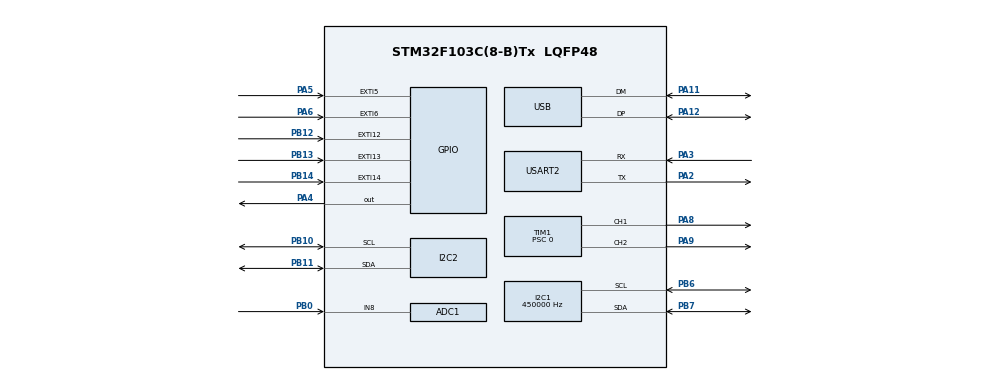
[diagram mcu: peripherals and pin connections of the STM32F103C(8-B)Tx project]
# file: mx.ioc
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ADC1.Channel-2\#ChannelRegularConversion=ADC_CHANNEL_8
ADC1.NbrOfConversionFlag=1
ADC1.Rank-2\#ChannelRegularConversion=1
ADC1.SamplingTime-2\#ChannelRegularConversion=ADC_SAMPLETIME_1CYCLE_5
ADC1.master=1
Dma.Request0=USART2_RX
Dma.USART2_RX.0.Direction=DMA_PERIPH_TO_MEMORY
Dma.USART2_RX.0.Instance=DMA1_Channel6
Dma.USART2_RX.0.MemDataAlignment=DMA_MDATAALIGN_BYTE
Dma.USART2_RX.0.MemInc=DMA_MINC_ENABLE
Dma.USART2_RX.0.Mode=DMA_NORMAL
Dma.USART2_RX.0.PeriphDataAlignment=DMA_PDATAALIGN_BYTE
Dma.USART2_RX.0.PeriphInc=DMA_PINC_DISABLE
Dma.USART2_RX.0.Priority=DMA_PRIORITY_MEDIUM
I2C1.ClockSpeed=450000
I2C1.I2C_Mode=I2C_Fast
Mcu.Family=STM32F1
Mcu.Name=STM32F103C(8-B)Tx
Mcu.Package=LQFP48
NVIC.ADC1_2_IRQn=true\:0\:0\:false\:false\:true\:true\:true\:true
NVIC.DMA1_Channel6_IRQn=true\:0\:0\:false\:false\:true\:false\:true\:true
NVIC.EXTI15_10_IRQn=true\:0\:0\:false\:false\:true\:true\:true\:true
NVIC.EXTI9_5_IRQn=true\:0\:0\:false\:false\:true\:true\:true\:true
NVIC.I2C1_ER_IRQn=true\:0\:0\:false\:false\:true\:true\:true\:true
NVIC.I2C1_EV_IRQn=true\:0\:0\:false\:false\:true\:true\:true\:true
NVIC.PriorityGroup=NVIC_PRIORITYGROUP_4
NVIC.TIM3_IRQn=true\:0\:0\:false\:false\:true\:true\:true\:true
NVIC.TIM4_IRQn=true\:0\:0\:false\:false\:true\:true\:true\:true
NVIC.USART2_IRQn=true\:0\:0\:false\:false\:true\:true\:true\:true
NVIC.USB_LP_CAN1_RX0_IRQn=true\:0\:0\:false\:false\:true\:false\:true\:true
PA11.Mode=Device
PA11.Signal=USB_DM
PA12.Mode=Device
PA12.Signal=USB_DP
PA13.Mode=Serial_Wire
PA13.Signal=SYS_JTMS-SWDIO
PA14.Mode=Serial_Wire
PA14.Signal=SYS_JTCK-SWCLK
PA2.Mode=Asynchronous
PA2.Signal=USART2_TX
PA3.Mode=Asynchronous
PA3.Signal=USART2_RX
PA4.GPIO_PuPd=GPIO_NOPULL
PA4.PinState=GPIO_PIN_RESET
PA4.Signal=GPIO_Output
PA5.GPIO_ModeDefaultEXTI=GPIO_MODE_IT_RISING_FALLING
PA5.GPIO_PuPd=GPIO_PULLUP
PA5.Signal=GPXTI5
PA6.GPIO_ModeDefaultEXTI=GPIO_MODE_IT_RISING_FALLING
PA6.GPIO_PuPd=GPIO_PULLUP
PA6.Signal=GPXTI6
PA8.GPIO_Speed=GPIO_SPEED_FREQ_MEDIUM
PA8.Signal=S_TIM1_CH1
PA9.GPIO_Speed=GPIO_SPEED_FREQ_MEDIUM
PA9.Signal=S_TIM1_CH2
PB0.Signal=ADCx_IN8
PB10.Mode=I2C
PB10.Signal=I2C2_SCL
PB11.Mode=I2C
PB11.Signal=I2C2_SDA
PB12.GPIO_ModeDefaultEXTI=GPIO_MODE_IT_RISING_FALLING
PB12.GPIO_PuPd=GPIO_PULLUP
PB12.Signal=GPXTI12
PB13.GPIO_ModeDefaultEXTI=GPIO_MODE_IT_RISING_FALLING
PB13.GPIO_PuPd=GPIO_PULLUP
PB13.Signal=GPXTI13
PB14.GPIO_ModeDefaultEXTI=GPIO_MODE_IT_RISING_FALLING
PB14.GPIO_PuPd=GPIO_PULLUP
PB14.Signal=GPXTI14
PB6.Mode=I2C
PB6.Signal=I2C1_SCL
PB7.Mode=I2C
PB7.Signal=I2C1_SDA
PD0-OSC_IN.Mode=HSE-External-Oscillator
PD0-OSC_IN.Signal=RCC_OSC_IN
PD1-OSC_OUT.Mode=HSE-External-Oscillator
PD1-OSC_OUT.Signal=RCC_OSC_OUT
ProjectManager.HeapSize=0x200
ProjectManager.StackSize=0x400
ProjectManager.TargetToolchain=CMake
RCC.ADCPresc=RCC_ADCPCLK2_DIV6
RCC.AHBFreq_Value=72000000
RCC.APB1CLKDivider=RCC_HCLK_DIV2
RCC.APB1Freq_Value=36000000
RCC.APB1TimFreq_Value=72000000
RCC.APB2Freq_Value=72000000
RCC.APB2TimFreq_Value=72000000
RCC.HCLKFreq_Value=72000000
RCC.PLLMUL=RCC_PLL_MUL9
RCC.PLLSourceVirtual=RCC_PLLSOURCE_HSE
RCC.SYSCLKFreq_VALUE=72000000
RCC.SYSCLKSource=RCC_SYSCLKSOURCE_PLLCLK
RCC.USBFreq_Value=48000000
RCC.USBPrescaler=RCC_USBCLKSOURCE_PLL_DIV1_5
SH.ADCx_IN8.0=ADC1_IN8,IN8
SH.S_TIM1_CH1.0=TIM1_CH1,PWM Generation1 CH1
SH.S_TIM1_CH2.0=TIM1_CH2,PWM Generation2 CH2
TIM1.Channel-PWM\ Generation1\ CH1=TIM_CHANNEL_1
TIM1.Channel-PWM\ Generation2\ CH2=TIM_CHANNEL_2
TIM1.OCMode_PWM-PWM\ Generation1\ CH1=TIM_OCMODE_PWM1
TIM1.Prescaler=0
TIM2.Prescaler=71
TIM3.Period=6300
TIM3.Prescaler=0
TIM4.Period=6200
TIM4.Prescaler=299
USART2.VirtualMode=VM_ASYNC
USB_DEVICE.CLASS_NAME_FS=HID
USB_DEVICE.VirtualMode=Hid
USB_DEVICE.VirtualModeFS=Hid_FS
VP_IWDG_VS_IWDG.Mode=IWDG_Activate
VP_TIM1_VS_ClockSourceINT.Mode=Internal
VP_TIM2_VS_ClockSourceINT.Mode=Internal
VP_TIM3_VS_ClockSourceINT.Mode=Internal
VP_TIM4_VS_ClockSourceINT.Mode=Internal
VP_USB_DEVICE_VS_USB_DEVICE_HID_FS.Mode=HID_FS
board=custom

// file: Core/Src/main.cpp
/* USER CODE BEGIN Header */
/**
 ******************************************************************************
 * @file           : main.c
 * @brief          : Main program body
 ******************************************************************************
 * @attention
 *
 * Copyright (c) 2025 STMicroelectronics.
 * All rights reserved.
 *
 * This software is licensed under terms that can be found in the LICENSE file
 * in the root directory of this software component.
 * If no LICENSE file comes with this software, it is provided AS-IS.
 *
 ******************************************************************************
 */
/* USER CODE END Header */
#include "main.h"
#include "adc.h"
#include "custom_types.h"
#include "dma.h"
#include "gpio.h"
#include "i2c.h"
#include "stm32f1xx_hal_iwdg.h"
#include "tim.h"
#include "usart.h"
#include "usb_device.h"

/* USER CODE BEGIN Includes */
#include "app.h"
#include "iwdg.h"
#include <sys/_types.h>
/* USER CODE END Includes */

void SystemClock_Config(void);

int main(void) {

  /* MCU Configuration--------------------------------------------------------*/

  /* Reset of all peripherals, Initializes the Flash interface and the Systick.
   */
  HAL_Init();

  /* Configure the system clock */
  SystemClock_Config();

  /* Initialize all configured peripherals */
  MX_GPIO_Init();
  MX_DMA_Init();
  MX_ADC1_Init();
  MX_I2C1_Init();
  MX_I2C2_Init();
  MX_TIM1_Init();
  MX_USB_DEVICE_Init();
  MX_USART2_UART_Init();
  MX_TIM2_Init();
  MX_TIM3_Init();
  HAL_TIM_Base_Start_IT(&htim3); // 启动定时器3中断
  MX_TIM4_Init();
  HAL_TIM_Base_Start_IT(&htim4); // 启动定时器4中断
  MX_IWDG_Init();
  /* USER CODE BEGIN 2 */

  // Initialize UART DMA reception
  UART_DMA_Init();
  UART_Start_DMA_Reception();

  // Initialize user application
  App_Init();

  /* USER CODE END 2 */

  /* Infinite loop */
  while (1) {

    /* USER CODE BEGIN 3 */

    // Call user application loop
    HAL_IWDG_Refresh(&hiwdg); // 喂狗

    // Process UART messages
    UART_Process_DMA_Reception();

    App_Loop();
  }
  /* USER CODE END 3 */
}

void SystemClock_Config(void) {
  RCC_OscInitTypeDef RCC_OscInitStruct = {0};
  RCC_ClkInitTypeDef RCC_ClkInitStruct = {0};
  RCC_PeriphCLKInitTypeDef PeriphClkInit = {0};

  /** Initializes the RCC Oscillators according to the specified parameters
   * in the RCC_OscInitTypeDef structure.
   */
  RCC_OscInitStruct.OscillatorType = RCC_OSCILLATORTYPE_HSE;
  RCC_OscInitStruct.HSEState = RCC_HSE_ON;
  RCC_OscInitStruct.HSEPredivValue = RCC_HSE_PREDIV_DIV1;
  RCC_OscInitStruct.HSIState = RCC_HSI_ON;
  RCC_OscInitStruct.PLL.PLLState = RCC_PLL_ON;
  RCC_OscInitStruct.PLL.PLLSource = RCC_PLLSOURCE_HSE;
  RCC_OscInitStruct.PLL.PLLMUL = RCC_PLL_MUL16;
  if (HAL_RCC_OscConfig(&RCC_OscInitStruct) != HAL_OK) {
    Error_Handler();
  }

  /** Initializes the CPU, AHB and APB buses clocks
   */
  RCC_ClkInitStruct.ClockType = RCC_CLOCKTYPE_HCLK | RCC_CLOCKTYPE_SYSCLK |
                                RCC_CLOCKTYPE_PCLK1 | RCC_CLOCKTYPE_PCLK2;
  RCC_ClkInitStruct.SYSCLKSource = RCC_SYSCLKSOURCE_PLLCLK;
  RCC_ClkInitStruct.AHBCLKDivider = RCC_SYSCLK_DIV1;
  RCC_ClkInitStruct.APB1CLKDivider = RCC_HCLK_DIV2;
  RCC_ClkInitStruct.APB2CLKDivider = RCC_HCLK_DIV1;

  if (HAL_RCC_ClockConfig(&RCC_ClkInitStruct, FLASH_LATENCY_2) != HAL_OK) {
    Error_Handler();
  }
  PeriphClkInit.PeriphClockSelection = RCC_PERIPHCLK_ADC | RCC_PERIPHCLK_USB;
  PeriphClkInit.AdcClockSelection = RCC_ADCPCLK2_DIV6;
  PeriphClkInit.UsbClockSelection = RCC_USBCLKSOURCE_PLL_DIV1_5;
  if (HAL_RCCEx_PeriphCLKConfig(&PeriphClkInit) != HAL_OK) {
    Error_Handler();
  }
}

/* USER CODE BEGIN 4 */

/**
 * @brief GPIO EXTI callback function
 * @param GPIO_Pin Pin that triggered the interrupt
 */
extern "C" void HAL_GPIO_EXTI_Callback(uint16_t GPIO_Pin) {
  // Get references to global objects
  extern RotaryEncoder rotary_encoder;
  extern Button encoder_button;
  extern Button btn_1;
  extern Button btn_2;

  // Handle encoder and button interrupts based on specific pins
  switch (GPIO_Pin) {
  case GPIO_PIN_12: // Encoder Pin A
  case GPIO_PIN_13: // Encoder Pin B
    rotary_encoder.onGpioInterrupt(GPIO_Pin);
    break;

  case GPIO_PIN_14: // Encoder Button
    encoder_button.onGpioInterrupt();
    break;

  case GPIO_PIN_5: // Button 1
    btn_1.onGpioInterrupt();
    break;

  case GPIO_PIN_6: // Button 2
    btn_2.onGpioInterrupt();
    break;

  default:
    // Unknown pin, ignore
    break;
  }
}

extern unsigned char adc_done_flag;
extern uint16_t adc_value; // ADC采样值
extern "C" void HAL_ADC_ConvCpltCallback(ADC_HandleTypeDef *hadc) {
  if (hadc == &hadc1) {
    adc_value = HAL_ADC_GetValue(hadc);
    // HAL_ADC_Start_IT(&hadc1); // 需要的时候再开启ADC
    adc_done_flag = 1; // 设置ADC完成标志
  }
}

// 用于计算频率的全局变量
extern "C" void HAL_TIM_PeriodElapsedCallback(TIM_HandleTypeDef *htim) {
  if (htim == &htim3) {
    // 每次中断发生时，计数器加1
    App_TIM3_IRQHandler();
  }
  if (htim == &htim4) {
    // 每次中断发生时，执行命令
    App_Command_Executor_Timer_Callback();
  }
}

/* USER CODE END 4 */

void Error_Handler(void) {
  __disable_irq();
  while (1) {
  }
}
#ifdef USE_FULL_ASSERT
/**
 * @brief  Reports the name of the source file and the source line number
 *         where the assert_param error has occurred.
 * @param  file: pointer to the source file name
 * @param  line: assert_param error line source number
 * @retval None
 */
void assert_failed(uint8_t *file, uint32_t line) {
  /* USER CODE BEGIN 6 */
  /* User can add his own implementation to report the file name and line
     number, ex: printf("Wrong parameters value: file %s on line %d\r\n", file,
     line) */
  /* USER CODE END 6 */
}
#endif /* USE_FULL_ASSERT */
